One B-rep face of a CAD part: STEP entity #19535.
In plain terms, the planar face has unit normal (0, 0, 1).
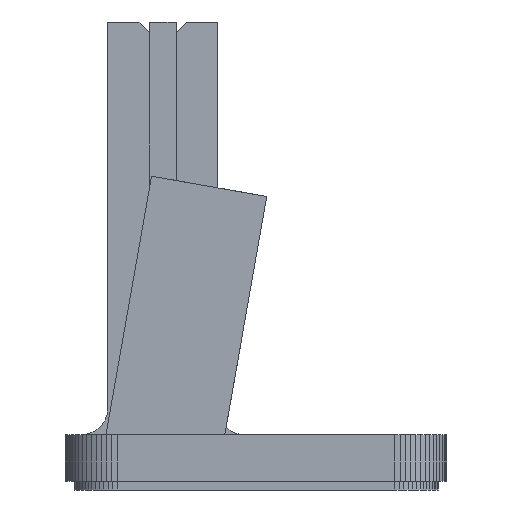
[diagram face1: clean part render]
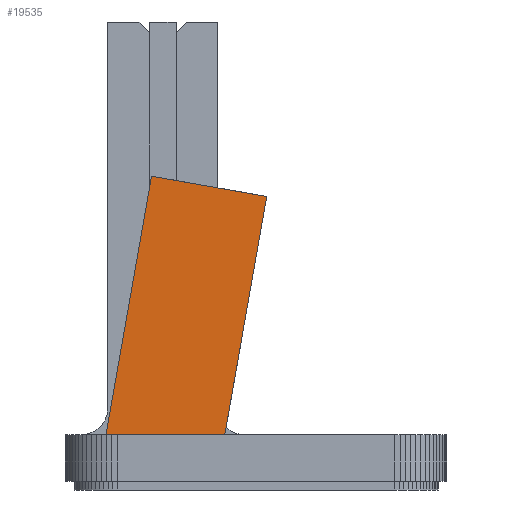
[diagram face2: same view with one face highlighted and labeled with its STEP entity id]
Its self-contained STEP definition (entity closure, numbers rounded to 3 decimals):
#144 = PLANE('',#145);
#145 = AXIS2_PLACEMENT_3D('',#146,#147,#148);
#146 = CARTESIAN_POINT('',(91.5,116.8,3.5));
#147 = DIRECTION('',(0.,-1.,0.));
#148 = DIRECTION('',(1.,0.,0.));
#19274 = PLANE('',#19275);
#19275 = AXIS2_PLACEMENT_3D('',#19276,#19277,#19278);
#19276 = CARTESIAN_POINT('',(89.085,131.068,
    25.568));
#19277 = DIRECTION('',(-0.174,-0.985,
    0.));
#19278 = DIRECTION('',(0.985,-0.174,
    0.));
#19302 = PLANE('',#19303);
#19303 = AXIS2_PLACEMENT_3D('',#19304,#19305,#19306);
#19304 = CARTESIAN_POINT('',(85.473,131.705,27.05));
#19305 = DIRECTION('',(0.985,-0.174,
    0.));
#19306 = DIRECTION('',(0.,0.,-1.));
#19466 = VERTEX_POINT('',#19467);
#19467 = CARTESIAN_POINT('',(85.473,131.705,27.05));
#19488 = EDGE_CURVE('',#19466,#19489,#19491,.T.);
#19489 = VERTEX_POINT('',#19490);
#19490 = CARTESIAN_POINT('',(82.844,116.8,27.05));
#19491 = SURFACE_CURVE('',#19492,(#19496,#19503),.PCURVE_S1.);
#19492 = LINE('',#19493,#19494);
#19493 = CARTESIAN_POINT('',(85.473,131.705,27.05));
#19494 = VECTOR('',#19495,1.);
#19495 = DIRECTION('',(-0.174,-0.985,
    0.));
#19496 = PCURVE('',#19302,#19497);
#19497 = DEFINITIONAL_REPRESENTATION('',(#19498),#19502);
#19498 = LINE('',#19499,#19500);
#19499 = CARTESIAN_POINT('',(0.,0.));
#19500 = VECTOR('',#19501,1.);
#19501 = DIRECTION('',(0.,-1.));
#19502 = ( GEOMETRIC_REPRESENTATION_CONTEXT(2) 
PARAMETRIC_REPRESENTATION_CONTEXT() REPRESENTATION_CONTEXT('2D SPACE',''
  ) );
#19503 = PCURVE('',#19504,#19509);
#19504 = PLANE('',#19505);
#19505 = AXIS2_PLACEMENT_3D('',#19506,#19507,#19508);
#19506 = CARTESIAN_POINT('',(92.12,130.533,27.05));
#19507 = DIRECTION('',(0.,0.,-1.));
#19508 = DIRECTION('',(-0.985,0.174,0.
    ));
#19509 = DEFINITIONAL_REPRESENTATION('',(#19510),#19514);
#19510 = LINE('',#19511,#19512);
#19511 = CARTESIAN_POINT('',(6.75,0.));
#19512 = VECTOR('',#19513,1.);
#19513 = DIRECTION('',(0.,-1.));
#19514 = ( GEOMETRIC_REPRESENTATION_CONTEXT(2) 
PARAMETRIC_REPRESENTATION_CONTEXT() REPRESENTATION_CONTEXT('2D SPACE',''
  ) );
#19535 = ADVANCED_FACE('',(#19536),#19504,.F.);
#19536 = FACE_BOUND('',#19537,.F.);
#19537 = EDGE_LOOP('',(#19538,#19561,#19589,#19608));
#19538 = ORIENTED_EDGE('',*,*,#19539,.F.);
#19539 = EDGE_CURVE('',#19540,#19466,#19542,.T.);
#19540 = VERTEX_POINT('',#19541);
#19541 = CARTESIAN_POINT('',(92.12,130.533,27.05));
#19542 = SURFACE_CURVE('',#19543,(#19547,#19554),.PCURVE_S1.);
#19543 = LINE('',#19544,#19545);
#19544 = CARTESIAN_POINT('',(92.12,130.533,27.05));
#19545 = VECTOR('',#19546,1.);
#19546 = DIRECTION('',(-0.985,0.174,0.
    ));
#19547 = PCURVE('',#19504,#19548);
#19548 = DEFINITIONAL_REPRESENTATION('',(#19549),#19553);
#19549 = LINE('',#19550,#19551);
#19550 = CARTESIAN_POINT('',(0.,-0.));
#19551 = VECTOR('',#19552,1.);
#19552 = DIRECTION('',(1.,0.));
#19553 = ( GEOMETRIC_REPRESENTATION_CONTEXT(2) 
PARAMETRIC_REPRESENTATION_CONTEXT() REPRESENTATION_CONTEXT('2D SPACE',''
  ) );
#19554 = PCURVE('',#19274,#19555);
#19555 = DEFINITIONAL_REPRESENTATION('',(#19556),#19560);
#19556 = LINE('',#19557,#19558);
#19557 = CARTESIAN_POINT('',(3.082,1.482));
#19558 = VECTOR('',#19559,1.);
#19559 = DIRECTION('',(-1.,0.));
#19560 = ( GEOMETRIC_REPRESENTATION_CONTEXT(2) 
PARAMETRIC_REPRESENTATION_CONTEXT() REPRESENTATION_CONTEXT('2D SPACE',''
  ) );
#19561 = ORIENTED_EDGE('',*,*,#19562,.T.);
#19562 = EDGE_CURVE('',#19540,#19563,#19565,.T.);
#19563 = VERTEX_POINT('',#19564);
#19564 = CARTESIAN_POINT('',(89.699,116.8,27.05));
#19565 = SURFACE_CURVE('',#19566,(#19570,#19577),.PCURVE_S1.);
#19566 = LINE('',#19567,#19568);
#19567 = CARTESIAN_POINT('',(92.12,130.533,27.05));
#19568 = VECTOR('',#19569,1.);
#19569 = DIRECTION('',(-0.174,-0.985,
    0.));
#19570 = PCURVE('',#19504,#19571);
#19571 = DEFINITIONAL_REPRESENTATION('',(#19572),#19576);
#19572 = LINE('',#19573,#19574);
#19573 = CARTESIAN_POINT('',(0.,-0.));
#19574 = VECTOR('',#19575,1.);
#19575 = DIRECTION('',(0.,-1.));
#19576 = ( GEOMETRIC_REPRESENTATION_CONTEXT(2) 
PARAMETRIC_REPRESENTATION_CONTEXT() REPRESENTATION_CONTEXT('2D SPACE',''
  ) );
#19577 = PCURVE('',#19578,#19583);
#19578 = PLANE('',#19579);
#19579 = AXIS2_PLACEMENT_3D('',#19580,#19581,#19582);
#19580 = CARTESIAN_POINT('',(89.88,117.829,23.15));
#19581 = DIRECTION('',(-0.985,0.174,0.
    ));
#19582 = DIRECTION('',(0.,0.,1.));
#19583 = DEFINITIONAL_REPRESENTATION('',(#19584),#19588);
#19584 = LINE('',#19585,#19586);
#19585 = CARTESIAN_POINT('',(3.9,12.9));
#19586 = VECTOR('',#19587,1.);
#19587 = DIRECTION('',(0.,-1.));
#19588 = ( GEOMETRIC_REPRESENTATION_CONTEXT(2) 
PARAMETRIC_REPRESENTATION_CONTEXT() REPRESENTATION_CONTEXT('2D SPACE',''
  ) );
#19589 = ORIENTED_EDGE('',*,*,#19590,.F.);
#19590 = EDGE_CURVE('',#19489,#19563,#19591,.T.);
#19591 = SURFACE_CURVE('',#19592,(#19596,#19602),.PCURVE_S1.);
#19592 = LINE('',#19593,#19594);
#19593 = CARTESIAN_POINT('',(91.81,116.8,27.05));
#19594 = VECTOR('',#19595,1.);
#19595 = DIRECTION('',(1.,0.,0.));
#19596 = PCURVE('',#19504,#19597);
#19597 = DEFINITIONAL_REPRESENTATION('',(#19598),#19601);
#19598 = B_SPLINE_CURVE_WITH_KNOTS('',1,(#19599,#19600),.UNSPECIFIED.,
  .F.,.F.,(2,2),(-8.966,-2.111),
  .PIECEWISE_BEZIER_KNOTS.);
#19599 = CARTESIAN_POINT('',(6.75,-15.135));
#19600 = CARTESIAN_POINT('',(0.,-13.945));
#19601 = ( GEOMETRIC_REPRESENTATION_CONTEXT(2) 
PARAMETRIC_REPRESENTATION_CONTEXT() REPRESENTATION_CONTEXT('2D SPACE',''
  ) );
#19602 = PCURVE('',#144,#19603);
#19603 = DEFINITIONAL_REPRESENTATION('',(#19604),#19607);
#19604 = B_SPLINE_CURVE_WITH_KNOTS('',1,(#19605,#19606),.UNSPECIFIED.,
  .F.,.F.,(2,2),(-8.966,-2.111),
  .PIECEWISE_BEZIER_KNOTS.);
#19605 = CARTESIAN_POINT('',(-8.656,23.55));
#19606 = CARTESIAN_POINT('',(-1.801,23.55));
#19607 = ( GEOMETRIC_REPRESENTATION_CONTEXT(2) 
PARAMETRIC_REPRESENTATION_CONTEXT() REPRESENTATION_CONTEXT('2D SPACE',''
  ) );
#19608 = ORIENTED_EDGE('',*,*,#19488,.F.);
